# OpenTallas memory compiler (tools/mem_compiler), ASAP7 abstract view, track-aligned v2 (build_hbm_rightwidth_1103.py)
VERSION 5.7 ;
BUSBITCHARS "[]" ;
DIVIDERCHAR "/" ;
PROPERTYDEFINITIONS
  MACRO width INTEGER ;
  MACRO depth INTEGER ;
  MACRO banks INTEGER ;
END PROPERTYDEFINITIONS
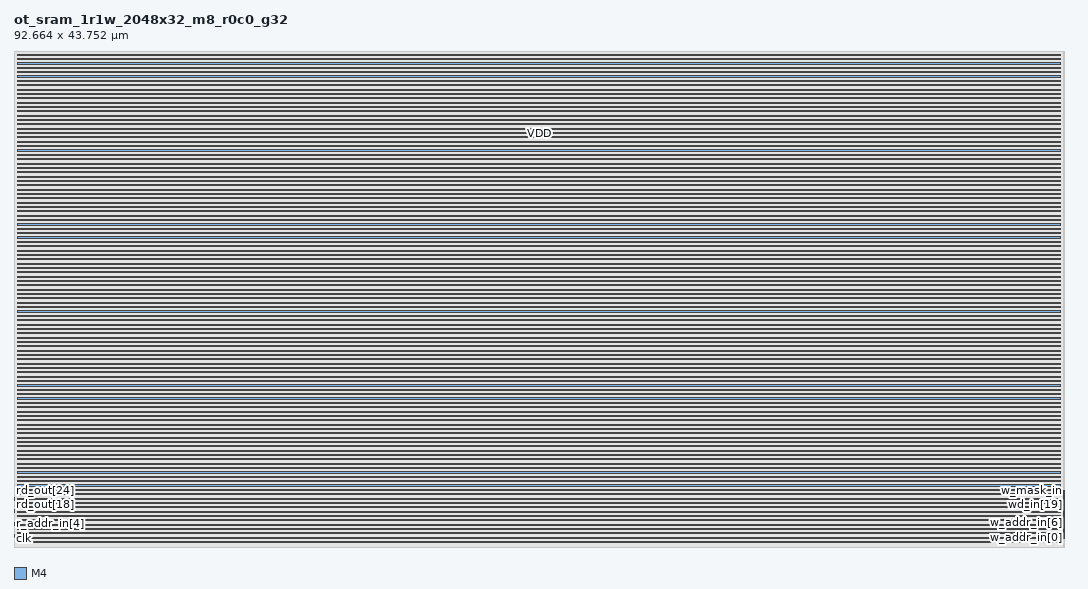
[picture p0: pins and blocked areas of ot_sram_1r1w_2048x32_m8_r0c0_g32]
MACRO ot_sram_1r1w_2048x32_m8_r0c0_g32
  PROPERTY width 32 ;
  PROPERTY depth 2048 ;
  PROPERTY banks 1 ;
  FOREIGN ot_sram_1r1w_2048x32_m8_r0c0_g32 0 0 ;
  SYMMETRY X Y ;
  SIZE 92.664 BY 43.752 ;
  CLASS BLOCK ;
  PIN clk
    DIRECTION INPUT ;
    USE CLOCK ;
    SHAPE ABUTMENT ;
    PORT
      LAYER M4 ;
      RECT 0.000 0.768 0.024 0.792 ;
    END
  END clk
  PIN r_ce_in
    DIRECTION INPUT ;
    USE SIGNAL ;
    SHAPE ABUTMENT ;
    PORT
      LAYER M4 ;
      RECT 0.000 0.864 0.024 0.888 ;
    END
  END r_ce_in
  PIN r_addr_in[0]
    DIRECTION INPUT ;
    USE SIGNAL ;
    SHAPE ABUTMENT ;
    PORT
      LAYER M4 ;
      RECT 0.000 0.960 0.024 0.984 ;
    END
  END r_addr_in[0]
  PIN r_addr_in[1]
    DIRECTION INPUT ;
    USE SIGNAL ;
    SHAPE ABUTMENT ;
    PORT
      LAYER M4 ;
      RECT 0.000 1.056 0.024 1.080 ;
    END
  END r_addr_in[1]
  PIN r_addr_in[2]
    DIRECTION INPUT ;
    USE SIGNAL ;
    SHAPE ABUTMENT ;
    PORT
      LAYER M4 ;
      RECT 0.000 1.152 0.024 1.176 ;
    END
  END r_addr_in[2]
  PIN r_addr_in[3]
    DIRECTION INPUT ;
    USE SIGNAL ;
    SHAPE ABUTMENT ;
    PORT
      LAYER M4 ;
      RECT 0.000 1.248 0.024 1.272 ;
    END
  END r_addr_in[3]
  PIN r_addr_in[4]
    DIRECTION INPUT ;
    USE SIGNAL ;
    SHAPE ABUTMENT ;
    PORT
      LAYER M4 ;
      RECT 0.000 1.344 0.024 1.368 ;
    END
  END r_addr_in[4]
  PIN r_addr_in[5]
    DIRECTION INPUT ;
    USE SIGNAL ;
    SHAPE ABUTMENT ;
    PORT
      LAYER M4 ;
      RECT 0.000 1.440 0.024 1.464 ;
    END
  END r_addr_in[5]
  PIN r_addr_in[6]
    DIRECTION INPUT ;
    USE SIGNAL ;
    SHAPE ABUTMENT ;
    PORT
      LAYER M4 ;
      RECT 0.000 1.536 0.024 1.560 ;
    END
  END r_addr_in[6]
  PIN r_addr_in[7]
    DIRECTION INPUT ;
    USE SIGNAL ;
    SHAPE ABUTMENT ;
    PORT
      LAYER M4 ;
      RECT 0.000 1.632 0.024 1.656 ;
    END
  END r_addr_in[7]
  PIN r_addr_in[8]
    DIRECTION INPUT ;
    USE SIGNAL ;
    SHAPE ABUTMENT ;
    PORT
      LAYER M4 ;
      RECT 0.000 1.728 0.024 1.752 ;
    END
  END r_addr_in[8]
  PIN r_addr_in[9]
    DIRECTION INPUT ;
    USE SIGNAL ;
    SHAPE ABUTMENT ;
    PORT
      LAYER M4 ;
      RECT 0.000 1.824 0.024 1.848 ;
    END
  END r_addr_in[9]
  PIN r_addr_in[10]
    DIRECTION INPUT ;
    USE SIGNAL ;
    SHAPE ABUTMENT ;
    PORT
      LAYER M4 ;
      RECT 0.000 1.920 0.024 1.944 ;
    END
  END r_addr_in[10]
  PIN rd_out[0]
    DIRECTION OUTPUT ;
    USE SIGNAL ;
    SHAPE ABUTMENT ;
    PORT
      LAYER M4 ;
      RECT 0.000 2.016 0.024 2.040 ;
    END
  END rd_out[0]
  PIN rd_out[1]
    DIRECTION OUTPUT ;
    USE SIGNAL ;
    SHAPE ABUTMENT ;
    PORT
      LAYER M4 ;
      RECT 0.000 2.112 0.024 2.136 ;
    END
  END rd_out[1]
  PIN rd_out[2]
    DIRECTION OUTPUT ;
    USE SIGNAL ;
    SHAPE ABUTMENT ;
    PORT
      LAYER M4 ;
      RECT 0.000 2.208 0.024 2.232 ;
    END
  END rd_out[2]
  PIN rd_out[3]
    DIRECTION OUTPUT ;
    USE SIGNAL ;
    SHAPE ABUTMENT ;
    PORT
      LAYER M4 ;
      RECT 0.000 2.304 0.024 2.328 ;
    END
  END rd_out[3]
  PIN rd_out[4]
    DIRECTION OUTPUT ;
    USE SIGNAL ;
    SHAPE ABUTMENT ;
    PORT
      LAYER M4 ;
      RECT 0.000 2.400 0.024 2.424 ;
    END
  END rd_out[4]
  PIN rd_out[5]
    DIRECTION OUTPUT ;
    USE SIGNAL ;
    SHAPE ABUTMENT ;
    PORT
      LAYER M4 ;
      RECT 0.000 2.496 0.024 2.520 ;
    END
  END rd_out[5]
  PIN rd_out[6]
    DIRECTION OUTPUT ;
    USE SIGNAL ;
    SHAPE ABUTMENT ;
    PORT
      LAYER M4 ;
      RECT 0.000 2.592 0.024 2.616 ;
    END
  END rd_out[6]
  PIN rd_out[7]
    DIRECTION OUTPUT ;
    USE SIGNAL ;
    SHAPE ABUTMENT ;
    PORT
      LAYER M4 ;
      RECT 0.000 2.688 0.024 2.712 ;
    END
  END rd_out[7]
  PIN rd_out[8]
    DIRECTION OUTPUT ;
    USE SIGNAL ;
    SHAPE ABUTMENT ;
    PORT
      LAYER M4 ;
      RECT 0.000 2.784 0.024 2.808 ;
    END
  END rd_out[8]
  PIN rd_out[9]
    DIRECTION OUTPUT ;
    USE SIGNAL ;
    SHAPE ABUTMENT ;
    PORT
      LAYER M4 ;
      RECT 0.000 2.880 0.024 2.904 ;
    END
  END rd_out[9]
  PIN rd_out[10]
    DIRECTION OUTPUT ;
    USE SIGNAL ;
    SHAPE ABUTMENT ;
    PORT
      LAYER M4 ;
      RECT 0.000 2.976 0.024 3.000 ;
    END
  END rd_out[10]
  PIN rd_out[11]
    DIRECTION OUTPUT ;
    USE SIGNAL ;
    SHAPE ABUTMENT ;
    PORT
      LAYER M4 ;
      RECT 0.000 3.072 0.024 3.096 ;
    END
  END rd_out[11]
  PIN rd_out[12]
    DIRECTION OUTPUT ;
    USE SIGNAL ;
    SHAPE ABUTMENT ;
    PORT
      LAYER M4 ;
      RECT 0.000 3.168 0.024 3.192 ;
    END
  END rd_out[12]
  PIN rd_out[13]
    DIRECTION OUTPUT ;
    USE SIGNAL ;
    SHAPE ABUTMENT ;
    PORT
      LAYER M4 ;
      RECT 0.000 3.264 0.024 3.288 ;
    END
  END rd_out[13]
  PIN rd_out[14]
    DIRECTION OUTPUT ;
    USE SIGNAL ;
    SHAPE ABUTMENT ;
    PORT
      LAYER M4 ;
      RECT 0.000 3.360 0.024 3.384 ;
    END
  END rd_out[14]
  PIN rd_out[15]
    DIRECTION OUTPUT ;
    USE SIGNAL ;
    SHAPE ABUTMENT ;
    PORT
      LAYER M4 ;
      RECT 0.000 3.456 0.024 3.480 ;
    END
  END rd_out[15]
  PIN rd_out[16]
    DIRECTION OUTPUT ;
    USE SIGNAL ;
    SHAPE ABUTMENT ;
    PORT
      LAYER M4 ;
      RECT 0.000 3.552 0.024 3.576 ;
    END
  END rd_out[16]
  PIN rd_out[17]
    DIRECTION OUTPUT ;
    USE SIGNAL ;
    SHAPE ABUTMENT ;
    PORT
      LAYER M4 ;
      RECT 0.000 3.648 0.024 3.672 ;
    END
  END rd_out[17]
  PIN rd_out[18]
    DIRECTION OUTPUT ;
    USE SIGNAL ;
    SHAPE ABUTMENT ;
    PORT
      LAYER M4 ;
      RECT 0.000 3.744 0.024 3.768 ;
    END
  END rd_out[18]
  PIN rd_out[19]
    DIRECTION OUTPUT ;
    USE SIGNAL ;
    SHAPE ABUTMENT ;
    PORT
      LAYER M4 ;
      RECT 0.000 3.840 0.024 3.864 ;
    END
  END rd_out[19]
  PIN rd_out[20]
    DIRECTION OUTPUT ;
    USE SIGNAL ;
    SHAPE ABUTMENT ;
    PORT
      LAYER M4 ;
      RECT 0.000 3.936 0.024 3.960 ;
    END
  END rd_out[20]
  PIN rd_out[21]
    DIRECTION OUTPUT ;
    USE SIGNAL ;
    SHAPE ABUTMENT ;
    PORT
      LAYER M4 ;
      RECT 0.000 4.032 0.024 4.056 ;
    END
  END rd_out[21]
  PIN rd_out[22]
    DIRECTION OUTPUT ;
    USE SIGNAL ;
    SHAPE ABUTMENT ;
    PORT
      LAYER M4 ;
      RECT 0.000 4.128 0.024 4.152 ;
    END
  END rd_out[22]
  PIN rd_out[23]
    DIRECTION OUTPUT ;
    USE SIGNAL ;
    SHAPE ABUTMENT ;
    PORT
      LAYER M4 ;
      RECT 0.000 4.224 0.024 4.248 ;
    END
  END rd_out[23]
  PIN rd_out[24]
    DIRECTION OUTPUT ;
    USE SIGNAL ;
    SHAPE ABUTMENT ;
    PORT
      LAYER M4 ;
      RECT 0.000 4.320 0.024 4.344 ;
    END
  END rd_out[24]
  PIN rd_out[25]
    DIRECTION OUTPUT ;
    USE SIGNAL ;
    SHAPE ABUTMENT ;
    PORT
      LAYER M4 ;
      RECT 0.000 4.416 0.024 4.440 ;
    END
  END rd_out[25]
  PIN rd_out[26]
    DIRECTION OUTPUT ;
    USE SIGNAL ;
    SHAPE ABUTMENT ;
    PORT
      LAYER M4 ;
      RECT 0.000 4.512 0.024 4.536 ;
    END
  END rd_out[26]
  PIN rd_out[27]
    DIRECTION OUTPUT ;
    USE SIGNAL ;
    SHAPE ABUTMENT ;
    PORT
      LAYER M4 ;
      RECT 0.000 4.608 0.024 4.632 ;
    END
  END rd_out[27]
  PIN rd_out[28]
    DIRECTION OUTPUT ;
    USE SIGNAL ;
    SHAPE ABUTMENT ;
    PORT
      LAYER M4 ;
      RECT 0.000 4.704 0.024 4.728 ;
    END
  END rd_out[28]
  PIN rd_out[29]
    DIRECTION OUTPUT ;
    USE SIGNAL ;
    SHAPE ABUTMENT ;
    PORT
      LAYER M4 ;
      RECT 0.000 4.800 0.024 4.824 ;
    END
  END rd_out[29]
  PIN rd_out[30]
    DIRECTION OUTPUT ;
    USE SIGNAL ;
    SHAPE ABUTMENT ;
    PORT
      LAYER M4 ;
      RECT 0.000 4.896 0.024 4.920 ;
    END
  END rd_out[30]
  PIN rd_out[31]
    DIRECTION OUTPUT ;
    USE SIGNAL ;
    SHAPE ABUTMENT ;
    PORT
      LAYER M4 ;
      RECT 0.000 4.992 0.024 5.016 ;
    END
  END rd_out[31]
  PIN w_ce_in
    DIRECTION INPUT ;
    USE SIGNAL ;
    SHAPE ABUTMENT ;
    PORT
      LAYER M4 ;
      RECT 92.640 0.768 92.664 0.792 ;
    END
  END w_ce_in
  PIN w_addr_in[0]
    DIRECTION INPUT ;
    USE SIGNAL ;
    SHAPE ABUTMENT ;
    PORT
      LAYER M4 ;
      RECT 92.640 0.864 92.664 0.888 ;
    END
  END w_addr_in[0]
  PIN w_addr_in[1]
    DIRECTION INPUT ;
    USE SIGNAL ;
    SHAPE ABUTMENT ;
    PORT
      LAYER M4 ;
      RECT 92.640 0.960 92.664 0.984 ;
    END
  END w_addr_in[1]
  PIN w_addr_in[2]
    DIRECTION INPUT ;
    USE SIGNAL ;
    SHAPE ABUTMENT ;
    PORT
      LAYER M4 ;
      RECT 92.640 1.056 92.664 1.080 ;
    END
  END w_addr_in[2]
  PIN w_addr_in[3]
    DIRECTION INPUT ;
    USE SIGNAL ;
    SHAPE ABUTMENT ;
    PORT
      LAYER M4 ;
      RECT 92.640 1.152 92.664 1.176 ;
    END
  END w_addr_in[3]
  PIN w_addr_in[4]
    DIRECTION INPUT ;
    USE SIGNAL ;
    SHAPE ABUTMENT ;
    PORT
      LAYER M4 ;
      RECT 92.640 1.248 92.664 1.272 ;
    END
  END w_addr_in[4]
  PIN w_addr_in[5]
    DIRECTION INPUT ;
    USE SIGNAL ;
    SHAPE ABUTMENT ;
    PORT
      LAYER M4 ;
      RECT 92.640 1.344 92.664 1.368 ;
    END
  END w_addr_in[5]
  PIN w_addr_in[6]
    DIRECTION INPUT ;
    USE SIGNAL ;
    SHAPE ABUTMENT ;
    PORT
      LAYER M4 ;
      RECT 92.640 1.440 92.664 1.464 ;
    END
  END w_addr_in[6]
  PIN w_addr_in[7]
    DIRECTION INPUT ;
    USE SIGNAL ;
    SHAPE ABUTMENT ;
    PORT
      LAYER M4 ;
      RECT 92.640 1.536 92.664 1.560 ;
    END
  END w_addr_in[7]
  PIN w_addr_in[8]
    DIRECTION INPUT ;
    USE SIGNAL ;
    SHAPE ABUTMENT ;
    PORT
      LAYER M4 ;
      RECT 92.640 1.632 92.664 1.656 ;
    END
  END w_addr_in[8]
  PIN w_addr_in[9]
    DIRECTION INPUT ;
    USE SIGNAL ;
    SHAPE ABUTMENT ;
    PORT
      LAYER M4 ;
      RECT 92.640 1.728 92.664 1.752 ;
    END
  END w_addr_in[9]
  PIN w_addr_in[10]
    DIRECTION INPUT ;
    USE SIGNAL ;
    SHAPE ABUTMENT ;
    PORT
      LAYER M4 ;
      RECT 92.640 1.824 92.664 1.848 ;
    END
  END w_addr_in[10]
  PIN wd_in[0]
    DIRECTION INPUT ;
    USE SIGNAL ;
    SHAPE ABUTMENT ;
    PORT
      LAYER M4 ;
      RECT 92.640 1.920 92.664 1.944 ;
    END
  END wd_in[0]
  PIN wd_in[1]
    DIRECTION INPUT ;
    USE SIGNAL ;
    SHAPE ABUTMENT ;
    PORT
      LAYER M4 ;
      RECT 92.640 2.016 92.664 2.040 ;
    END
  END wd_in[1]
  PIN wd_in[2]
    DIRECTION INPUT ;
    USE SIGNAL ;
    SHAPE ABUTMENT ;
    PORT
      LAYER M4 ;
      RECT 92.640 2.112 92.664 2.136 ;
    END
  END wd_in[2]
  PIN wd_in[3]
    DIRECTION INPUT ;
    USE SIGNAL ;
    SHAPE ABUTMENT ;
    PORT
      LAYER M4 ;
      RECT 92.640 2.208 92.664 2.232 ;
    END
  END wd_in[3]
  PIN wd_in[4]
    DIRECTION INPUT ;
    USE SIGNAL ;
    SHAPE ABUTMENT ;
    PORT
      LAYER M4 ;
      RECT 92.640 2.304 92.664 2.328 ;
    END
  END wd_in[4]
  PIN wd_in[5]
    DIRECTION INPUT ;
    USE SIGNAL ;
    SHAPE ABUTMENT ;
    PORT
      LAYER M4 ;
      RECT 92.640 2.400 92.664 2.424 ;
    END
  END wd_in[5]
  PIN wd_in[6]
    DIRECTION INPUT ;
    USE SIGNAL ;
    SHAPE ABUTMENT ;
    PORT
      LAYER M4 ;
      RECT 92.640 2.496 92.664 2.520 ;
    END
  END wd_in[6]
  PIN wd_in[7]
    DIRECTION INPUT ;
    USE SIGNAL ;
    SHAPE ABUTMENT ;
    PORT
      LAYER M4 ;
      RECT 92.640 2.592 92.664 2.616 ;
    END
  END wd_in[7]
  PIN wd_in[8]
    DIRECTION INPUT ;
    USE SIGNAL ;
    SHAPE ABUTMENT ;
    PORT
      LAYER M4 ;
      RECT 92.640 2.688 92.664 2.712 ;
    END
  END wd_in[8]
  PIN wd_in[9]
    DIRECTION INPUT ;
    USE SIGNAL ;
    SHAPE ABUTMENT ;
    PORT
      LAYER M4 ;
      RECT 92.640 2.784 92.664 2.808 ;
    END
  END wd_in[9]
  PIN wd_in[10]
    DIRECTION INPUT ;
    USE SIGNAL ;
    SHAPE ABUTMENT ;
    PORT
      LAYER M4 ;
      RECT 92.640 2.880 92.664 2.904 ;
    END
  END wd_in[10]
  PIN wd_in[11]
    DIRECTION INPUT ;
    USE SIGNAL ;
    SHAPE ABUTMENT ;
    PORT
      LAYER M4 ;
      RECT 92.640 2.976 92.664 3.000 ;
    END
  END wd_in[11]
  PIN wd_in[12]
    DIRECTION INPUT ;
    USE SIGNAL ;
    SHAPE ABUTMENT ;
    PORT
      LAYER M4 ;
      RECT 92.640 3.072 92.664 3.096 ;
    END
  END wd_in[12]
  PIN wd_in[13]
    DIRECTION INPUT ;
    USE SIGNAL ;
    SHAPE ABUTMENT ;
    PORT
      LAYER M4 ;
      RECT 92.640 3.168 92.664 3.192 ;
    END
  END wd_in[13]
  PIN wd_in[14]
    DIRECTION INPUT ;
    USE SIGNAL ;
    SHAPE ABUTMENT ;
    PORT
      LAYER M4 ;
      RECT 92.640 3.264 92.664 3.288 ;
    END
  END wd_in[14]
  PIN wd_in[15]
    DIRECTION INPUT ;
    USE SIGNAL ;
    SHAPE ABUTMENT ;
    PORT
      LAYER M4 ;
      RECT 92.640 3.360 92.664 3.384 ;
    END
  END wd_in[15]
  PIN wd_in[16]
    DIRECTION INPUT ;
    USE SIGNAL ;
    SHAPE ABUTMENT ;
    PORT
      LAYER M4 ;
      RECT 92.640 3.456 92.664 3.480 ;
    END
  END wd_in[16]
  PIN wd_in[17]
    DIRECTION INPUT ;
    USE SIGNAL ;
    SHAPE ABUTMENT ;
    PORT
      LAYER M4 ;
      RECT 92.640 3.552 92.664 3.576 ;
    END
  END wd_in[17]
  PIN wd_in[18]
    DIRECTION INPUT ;
    USE SIGNAL ;
    SHAPE ABUTMENT ;
    PORT
      LAYER M4 ;
      RECT 92.640 3.648 92.664 3.672 ;
    END
  END wd_in[18]
  PIN wd_in[19]
    DIRECTION INPUT ;
    USE SIGNAL ;
    SHAPE ABUTMENT ;
    PORT
      LAYER M4 ;
      RECT 92.640 3.744 92.664 3.768 ;
    END
  END wd_in[19]
  PIN wd_in[20]
    DIRECTION INPUT ;
    USE SIGNAL ;
    SHAPE ABUTMENT ;
    PORT
      LAYER M4 ;
      RECT 92.640 3.840 92.664 3.864 ;
    END
  END wd_in[20]
  PIN wd_in[21]
    DIRECTION INPUT ;
    USE SIGNAL ;
    SHAPE ABUTMENT ;
    PORT
      LAYER M4 ;
      RECT 92.640 3.936 92.664 3.960 ;
    END
  END wd_in[21]
  PIN wd_in[22]
    DIRECTION INPUT ;
    USE SIGNAL ;
    SHAPE ABUTMENT ;
    PORT
      LAYER M4 ;
      RECT 92.640 4.032 92.664 4.056 ;
    END
  END wd_in[22]
  PIN wd_in[23]
    DIRECTION INPUT ;
    USE SIGNAL ;
    SHAPE ABUTMENT ;
    PORT
      LAYER M4 ;
      RECT 92.640 4.128 92.664 4.152 ;
    END
  END wd_in[23]
  PIN wd_in[24]
    DIRECTION INPUT ;
    USE SIGNAL ;
    SHAPE ABUTMENT ;
    PORT
      LAYER M4 ;
      RECT 92.640 4.224 92.664 4.248 ;
    END
  END wd_in[24]
  PIN wd_in[25]
    DIRECTION INPUT ;
    USE SIGNAL ;
    SHAPE ABUTMENT ;
    PORT
      LAYER M4 ;
      RECT 92.640 4.320 92.664 4.344 ;
    END
  END wd_in[25]
  PIN wd_in[26]
    DIRECTION INPUT ;
    USE SIGNAL ;
    SHAPE ABUTMENT ;
    PORT
      LAYER M4 ;
      RECT 92.640 4.416 92.664 4.440 ;
    END
  END wd_in[26]
  PIN wd_in[27]
    DIRECTION INPUT ;
    USE SIGNAL ;
    SHAPE ABUTMENT ;
    PORT
      LAYER M4 ;
      RECT 92.640 4.512 92.664 4.536 ;
    END
  END wd_in[27]
  PIN wd_in[28]
    DIRECTION INPUT ;
    USE SIGNAL ;
    SHAPE ABUTMENT ;
    PORT
      LAYER M4 ;
      RECT 92.640 4.608 92.664 4.632 ;
    END
  END wd_in[28]
  PIN wd_in[29]
    DIRECTION INPUT ;
    USE SIGNAL ;
    SHAPE ABUTMENT ;
    PORT
      LAYER M4 ;
      RECT 92.640 4.704 92.664 4.728 ;
    END
  END wd_in[29]
  PIN wd_in[30]
    DIRECTION INPUT ;
    USE SIGNAL ;
    SHAPE ABUTMENT ;
    PORT
      LAYER M4 ;
      RECT 92.640 4.800 92.664 4.824 ;
    END
  END wd_in[30]
  PIN wd_in[31]
    DIRECTION INPUT ;
    USE SIGNAL ;
    SHAPE ABUTMENT ;
    PORT
      LAYER M4 ;
      RECT 92.640 4.896 92.664 4.920 ;
    END
  END wd_in[31]
  PIN w_mask_in
    DIRECTION INPUT ;
    USE SIGNAL ;
    SHAPE ABUTMENT ;
    PORT
      LAYER M4 ;
      RECT 92.640 4.992 92.664 5.016 ;
    END
  END w_mask_in
  PIN VDD
    DIRECTION INOUT ;
    USE POWER ;
    PORT
      LAYER M4 ;
      RECT 0.300 0.384 92.364 0.480 ;
      RECT 0.300 1.152 92.364 1.248 ;
      RECT 0.300 1.920 92.364 2.016 ;
      RECT 0.300 2.688 92.364 2.784 ;
      RECT 0.300 3.456 92.364 3.552 ;
      RECT 0.300 4.224 92.364 4.320 ;
      RECT 0.300 4.992 92.364 5.088 ;
      RECT 0.300 5.760 92.364 5.856 ;
      RECT 0.300 6.528 92.364 6.624 ;
      RECT 0.300 7.296 92.364 7.392 ;
      RECT 0.300 8.064 92.364 8.160 ;
      RECT 0.300 8.832 92.364 8.928 ;
      RECT 0.300 9.600 92.364 9.696 ;
      RECT 0.300 10.368 92.364 10.464 ;
      RECT 0.300 11.136 92.364 11.232 ;
      RECT 0.300 11.904 92.364 12.000 ;
      RECT 0.300 12.672 92.364 12.768 ;
      RECT 0.300 13.440 92.364 13.536 ;
      RECT 0.300 14.208 92.364 14.304 ;
      RECT 0.300 14.976 92.364 15.072 ;
      RECT 0.300 15.744 92.364 15.840 ;
      RECT 0.300 16.512 92.364 16.608 ;
      RECT 0.300 17.280 92.364 17.376 ;
      RECT 0.300 18.048 92.364 18.144 ;
      RECT 0.300 18.816 92.364 18.912 ;
      RECT 0.300 19.584 92.364 19.680 ;
      RECT 0.300 20.352 92.364 20.448 ;
      RECT 0.300 21.120 92.364 21.216 ;
      RECT 0.300 21.888 92.364 21.984 ;
      RECT 0.300 22.656 92.364 22.752 ;
      RECT 0.300 23.424 92.364 23.520 ;
      RECT 0.300 24.192 92.364 24.288 ;
      RECT 0.300 24.960 92.364 25.056 ;
      RECT 0.300 25.728 92.364 25.824 ;
      RECT 0.300 26.496 92.364 26.592 ;
      RECT 0.300 27.264 92.364 27.360 ;
      RECT 0.300 28.032 92.364 28.128 ;
      RECT 0.300 28.800 92.364 28.896 ;
      RECT 0.300 29.568 92.364 29.664 ;
      RECT 0.300 30.336 92.364 30.432 ;
      RECT 0.300 31.104 92.364 31.200 ;
      RECT 0.300 31.872 92.364 31.968 ;
      RECT 0.300 32.640 92.364 32.736 ;
      RECT 0.300 33.408 92.364 33.504 ;
      RECT 0.300 34.176 92.364 34.272 ;
      RECT 0.300 34.944 92.364 35.040 ;
      RECT 0.300 35.712 92.364 35.808 ;
      RECT 0.300 36.480 92.364 36.576 ;
      RECT 0.300 37.248 92.364 37.344 ;
      RECT 0.300 38.016 92.364 38.112 ;
      RECT 0.300 38.784 92.364 38.880 ;
      RECT 0.300 39.552 92.364 39.648 ;
      RECT 0.300 40.320 92.364 40.416 ;
      RECT 0.300 41.088 92.364 41.184 ;
      RECT 0.300 41.856 92.364 41.952 ;
      RECT 0.300 42.624 92.364 42.720 ;
      RECT 0.300 43.392 92.364 43.488 ;
    END
  END VDD
  PIN VSS
    DIRECTION INOUT ;
    USE GROUND ;
    PORT
      LAYER M4 ;
      RECT 0.300 0.768 92.364 0.864 ;
      RECT 0.300 1.536 92.364 1.632 ;
      RECT 0.300 2.304 92.364 2.400 ;
      RECT 0.300 3.072 92.364 3.168 ;
      RECT 0.300 3.840 92.364 3.936 ;
      RECT 0.300 4.608 92.364 4.704 ;
      RECT 0.300 5.376 92.364 5.472 ;
      RECT 0.300 6.144 92.364 6.240 ;
      RECT 0.300 6.912 92.364 7.008 ;
      RECT 0.300 7.680 92.364 7.776 ;
      RECT 0.300 8.448 92.364 8.544 ;
      RECT 0.300 9.216 92.364 9.312 ;
      RECT 0.300 9.984 92.364 10.080 ;
      RECT 0.300 10.752 92.364 10.848 ;
      RECT 0.300 11.520 92.364 11.616 ;
      RECT 0.300 12.288 92.364 12.384 ;
      RECT 0.300 13.056 92.364 13.152 ;
      RECT 0.300 13.824 92.364 13.920 ;
      RECT 0.300 14.592 92.364 14.688 ;
      RECT 0.300 15.360 92.364 15.456 ;
      RECT 0.300 16.128 92.364 16.224 ;
      RECT 0.300 16.896 92.364 16.992 ;
      RECT 0.300 17.664 92.364 17.760 ;
      RECT 0.300 18.432 92.364 18.528 ;
      RECT 0.300 19.200 92.364 19.296 ;
      RECT 0.300 19.968 92.364 20.064 ;
      RECT 0.300 20.736 92.364 20.832 ;
      RECT 0.300 21.504 92.364 21.600 ;
      RECT 0.300 22.272 92.364 22.368 ;
      RECT 0.300 23.040 92.364 23.136 ;
      RECT 0.300 23.808 92.364 23.904 ;
      RECT 0.300 24.576 92.364 24.672 ;
      RECT 0.300 25.344 92.364 25.440 ;
      RECT 0.300 26.112 92.364 26.208 ;
      RECT 0.300 26.880 92.364 26.976 ;
      RECT 0.300 27.648 92.364 27.744 ;
      RECT 0.300 28.416 92.364 28.512 ;
      RECT 0.300 29.184 92.364 29.280 ;
      RECT 0.300 29.952 92.364 30.048 ;
      RECT 0.300 30.720 92.364 30.816 ;
      RECT 0.300 31.488 92.364 31.584 ;
      RECT 0.300 32.256 92.364 32.352 ;
      RECT 0.300 33.024 92.364 33.120 ;
      RECT 0.300 33.792 92.364 33.888 ;
      RECT 0.300 34.560 92.364 34.656 ;
      RECT 0.300 35.328 92.364 35.424 ;
      RECT 0.300 36.096 92.364 36.192 ;
      RECT 0.300 36.864 92.364 36.960 ;
      RECT 0.300 37.632 92.364 37.728 ;
      RECT 0.300 38.400 92.364 38.496 ;
      RECT 0.300 39.168 92.364 39.264 ;
      RECT 0.300 39.936 92.364 40.032 ;
      RECT 0.300 40.704 92.364 40.800 ;
      RECT 0.300 41.472 92.364 41.568 ;
      RECT 0.300 42.240 92.364 42.336 ;
      RECT 0.300 43.008 92.364 43.104 ;
    END
  END VSS
  OBS
    LAYER M1 ;
    RECT 0 0 92.664 43.752 ;
    LAYER M2 ;
    RECT 0 0 92.664 43.752 ;
    LAYER M3 ;
    RECT 0 0 92.664 43.752 ;
    LAYER M4 ;
    RECT 0.072 0 92.592 43.752 ;
  END
END ot_sram_1r1w_2048x32_m8_r0c0_g32

END LIBRARY
